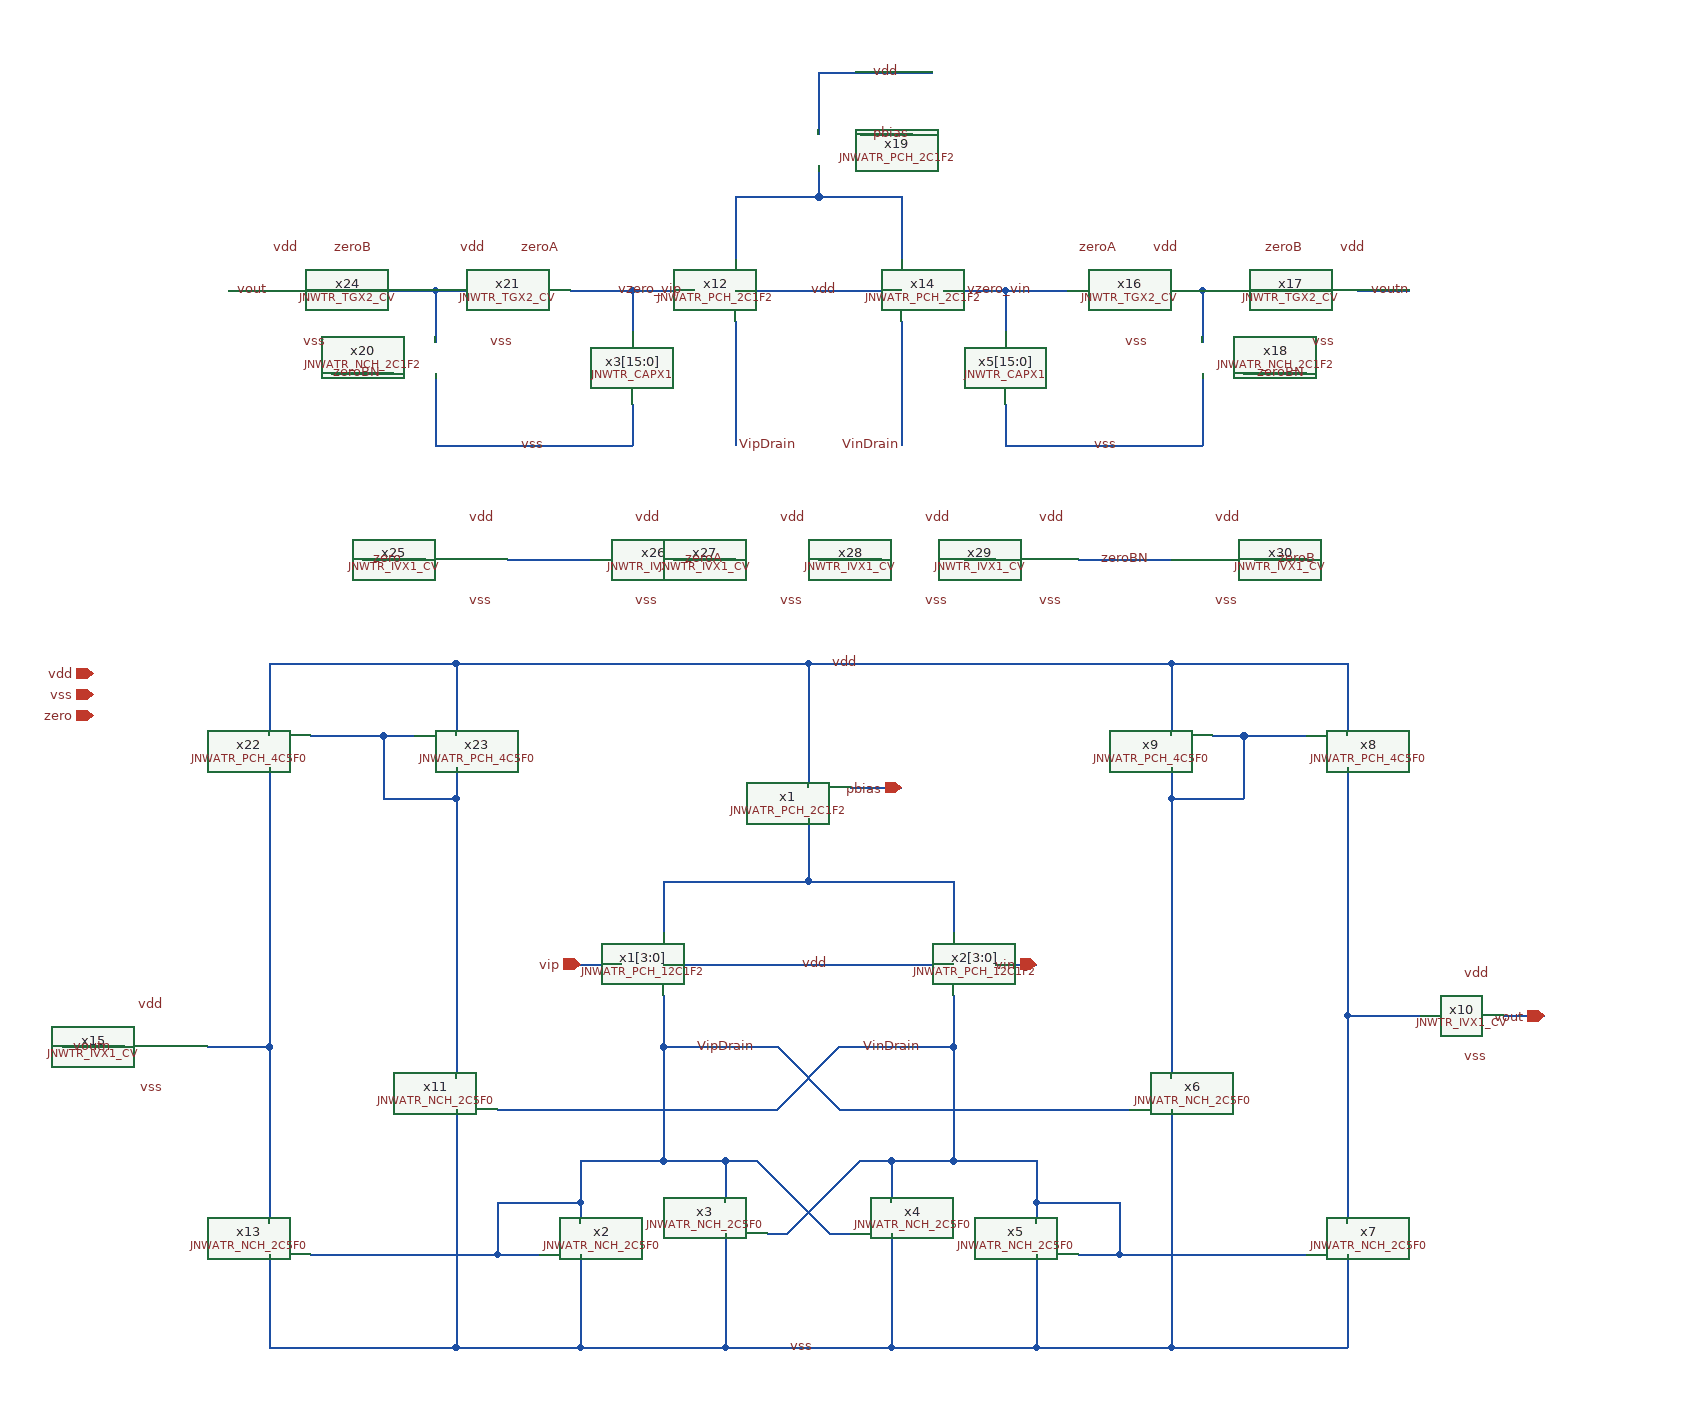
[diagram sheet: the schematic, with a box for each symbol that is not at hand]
v {xschem version=3.4.6RC file_version=1.2
}
G {}
K {}
V {}
S {}
E {}
N 1590 -800 1590 -740 {
lab=#net1}
N 1630 -830 1680 -830 {
lab=pbias}
N 1370 -660 1410 -660 {
lab=vip}
N 1770 -660 1810 -660 {
lab=vin}
N 1450 -580 1450 -470 {
lab=VipDrain}
N 1370 -430 1370 -410 {
lab=VipDrain}
N 1370 -470 1450 -470 {
lab=VipDrain}
N 1450 -470 1510 -470 {
lab=VipDrain}
N 1510 -470 1510 -430 {
lab=VipDrain}
N 1730 -580 1730 -470 {
lab=VinDrain}
N 1670 -470 1670 -430 {
lab=VinDrain}
N 1670 -470 1730 -470 {
lab=VinDrain}
N 1730 -470 1810 -470 {
lab=VinDrain}
N 1810 -430 1810 -410 {
lab=VinDrain}
N 1550 -400 1570 -400 {
lab=VinDrain}
N 1570 -400 1640 -470 {
lab=VinDrain}
N 1610 -400 1630 -400 {
lab=VipDrain}
N 1540 -470 1610 -400 {
lab=VipDrain}
N 1510 -470 1540 -470 {
lab=VipDrain}
N 1640 -470 1670 -470 {
lab=VinDrain}
N 1510 -400 1510 -290 {
lab=vss}
N 1670 -400 1670 -290 {
lab=vss}
N 1370 -290 1510 -290 {
lab=vss}
N 1510 -290 1670 -290 {
lab=vss}
N 1670 -290 1810 -290 {
lab=vss}
N 1810 -380 1810 -290 {
lab=vss}
N 1370 -380 1370 -290 {
lab=vss}
N 1890 -430 1890 -380 {
lab=VinDrain}
N 1810 -430 1890 -430 {
lab=VinDrain}
N 1810 -470 1810 -430 {
lab=VinDrain}
N 1850 -380 1890 -380 {
lab=VinDrain}
N 2110 -380 2110 -290 {
lab=vss}
N 2010 -880 2010 -820 {
lab=#net2}
N 2010 -880 2070 -880 {
lab=#net2}
N 1940 -950 1940 -880 {
lab=vdd}
N 2110 -950 2110 -880 {
lab=vdd}
N 1250 -950 1590 -950 {
lab=vdd}
N 1250 -290 1370 -290 {
lab=vss}
N 1590 -950 1590 -830 {
lab=vdd}
N 1450 -740 1450 -690 {
lab=#net1}
N 1730 -740 1730 -690 {
lab=#net1}
N 1450 -660 1730 -660 {
lab=vdd}
N 1450 -740 1590 -740 {
lab=#net1}
N 1590 -740 1730 -740 {
lab=#net1}
N 1940 -950 2110 -950 {
lab=vdd}
N 1940 -850 1940 -820 {
lab=#net2}
N 1940 -820 2010 -820 {
lab=#net2}
N 1890 -380 2070 -380 {
lab=VinDrain}
N 1590 -950 1940 -950 {
lab=vdd}
N 1940 -290 2110 -290 {
lab=vss}
N 1940 -820 1940 -550 {
lab=#net2}
N 1940 -520 1940 -290 {
lab=vss}
N 1810 -290 1940 -290 {
lab=vss}
N 1620 -520 1900 -520 {
lab=VipDrain}
N 1560 -580 1620 -520 {
lab=VipDrain}
N 1450 -580 1560 -580 {
lab=VipDrain}
N 1450 -630 1450 -580 {
lab=VipDrain}
N 1980 -880 2010 -880 {
lab=#net2}
N 1070 -380 1070 -290 {
lab=vss}
N 1180 -880 1180 -820 {
lab=#net3}
N 1110 -880 1180 -880 {
lab=#net3}
N 1250 -950 1250 -880 {
lab=vdd}
N 1070 -950 1070 -880 {
lab=vdd}
N 1070 -950 1250 -950 {
lab=vdd}
N 1250 -850 1250 -820 {
lab=#net3}
N 1070 -580 1070 -410 {
lab=#net4}
N 1180 -820 1250 -820 {
lab=#net3}
N 1070 -290 1250 -290 {
lab=vss}
N 1250 -820 1250 -550 {
lab=#net3}
N 1250 -520 1250 -290 {
lab=vss}
N 1180 -880 1210 -880 {
lab=#net3}
N 1290 -380 1330 -380 {
lab=VipDrain}
N 1290 -430 1290 -380 {
lab=VipDrain}
N 1110 -380 1290 -380 {
lab=VipDrain}
N 1290 -430 1370 -430 {
lab=VipDrain}
N 1370 -470 1370 -430 {
lab=VipDrain}
N 1290 -520 1560 -520 {
lab=VinDrain}
N 1560 -520 1620 -580 {
lab=VinDrain}
N 1620 -580 1730 -580 {
lab=VinDrain}
N 1730 -630 1730 -580 {
lab=VinDrain}
N 1010 -580 1070 -580 {
lab=#net4}
N 1070 -850 1070 -580 {
lab=#net4}
N 2110 -610 2110 -410 {
lab=#net5}
N 2110 -610 2180 -610 {
lab=#net5}
N 2110 -850 2110 -610 {
lab=#net5}
N 2120 -1310 2170 -1310 {
lab=voutn}
N 1600 -1400 1680 -1400 {
lab=#net6}
N 1600 -1430 1600 -1400 {
lab=#net6}
N 1640 -1460 1690 -1460 {
lab=pbias}
N 1520 -1400 1600 -1400 {
lab=#net6}
N 1600 -1520 1600 -1460 {
lab=vdd}
N 1600 -1520 1710 -1520 {
lab=vdd}
N 1720 -1310 1780 -1310 {
lab=vzero_vin}
N 1780 -1310 1780 -1270 {
lab=vzero_vin}
N 1780 -1310 1840 -1310 {
lab=vzero_vin}
N 1970 -1310 2020 -1310 {
lab=#net7}
N 1970 -1310 1970 -1260 {
lab=#net7}
N 1940 -1310 1970 -1310 {
lab=#net7}
N 1970 -1230 1970 -1160 {
lab=vss}
N 1780 -1160 1970 -1160 {
lab=vss}
N 1780 -1200 1780 -1160 {
lab=vss}
N 1030 -1310 1080 -1310 {
lab=vout}
N 1420 -1310 1480 -1310 {
lab=vzero_vip}
N 1420 -1310 1420 -1270 {
lab=vzero_vip}
N 1360 -1310 1420 -1310 {
lab=vzero_vip}
N 1180 -1310 1230 -1310 {
lab=#net8}
N 1230 -1310 1230 -1260 {
lab=#net8}
N 1230 -1310 1260 -1310 {
lab=#net8}
N 1230 -1230 1230 -1160 {
lab=vss}
N 1230 -1160 1420 -1160 {
lab=vss}
N 1420 -1200 1420 -1160 {
lab=vss}
N 1520 -1310 1680 -1310 {
lab=vdd}
N 1520 -1400 1520 -1340 {
lab=#net6}
N 1680 -1400 1680 -1340 {
lab=#net6}
N 1520 -1280 1520 -1160 {
lab=VipDrain}
N 1680 -1280 1680 -1160 {
lab=VinDrain}
N 1300 -1050 1380 -1050 {
lab=#net9}
N 1460 -1050 1520 -1050 {
lab=zeroA}
N 1600 -1050 1660 -1050 {
lab=#net10}
N 1740 -1050 1770 -1050 {
lab=#net11}
N 1850 -1050 1940 -1050 {
lab=zeroBN}
N 2020 -1050 2070 -1050 {
lab=zeroB}
N 1160 -1050 1220 -1050 {
lab=zero}
N 2010 -1230 2070 -1230 {
lab=zeroBN}
N 1130 -1230 1190 -1230 {
lab=zeroBN}
N 2260 -610 2300 -610 {
lab=vout}
N 870 -580 930 -580 {
lab=voutn}
C {devices/ipin.sym} 900 -920 0 0 {name=p2 lab=vss
}
C {devices/ipin.sym} 900 -940 0 0 {name=p3 lab=vdd
}
C {JNW_ATR_SKY130A/JNWATR_PCH_12C1F2.sym} 1410 -660 0 0 {name=x1[3:0]}
C {JNW_ATR_SKY130A/JNWATR_PCH_12C1F2.sym} 1770 -660 0 1 {name=x2[3:0]}
C {devices/ipin.sym} 1680 -830 2 0 {name=p1 lab=pbias
}
C {JNW_ATR_SKY130A/JNWATR_PCH_2C1F2.sym} 1630 -830 0 1 {name=x1}
C {devices/ipin.sym} 1810 -660 2 0 {name=p5 lab=vin
}
C {devices/ipin.sym} 1370 -660 0 0 {name=p6 lab=vip
}
C {JNW_ATR_SKY130A/JNWATR_NCH_2C5F0.sym} 1330 -380 0 0 {name=x2 }
C {JNW_ATR_SKY130A/JNWATR_NCH_2C5F0.sym} 1550 -400 0 1 {name=x3 }
C {JNW_ATR_SKY130A/JNWATR_NCH_2C5F0.sym} 1630 -400 0 0 {name=x4 }
C {JNW_ATR_SKY130A/JNWATR_NCH_2C5F0.sym} 1850 -380 0 1 {name=x5 }
C {JNW_ATR_SKY130A/JNWATR_NCH_2C5F0.sym} 1900 -520 0 0 {name=x6 }
C {JNW_ATR_SKY130A/JNWATR_NCH_2C5F0.sym} 2070 -380 0 0 {name=x7 }
C {JNW_ATR_SKY130A/JNWATR_PCH_4C5F0.sym} 2070 -880 0 0 {name=x8 }
C {JNW_ATR_SKY130A/JNWATR_PCH_4C5F0.sym} 1980 -880 0 1 {name=x9 }
C {devices/opin.sym} 2300 -610 2 1 {name=p7 lab=vout}
C {devices/lab_wire.sym} 1610 -660 0 0 {name=p4 sig_type=std_logic lab=vdd}
C {JNW_TR_SKY130A/JNWTR_IVX1_CV.sym} 2180 -610 0 0 {name=x10 }
C {devices/lab_wire.sym} 2220 -650 0 1 {name=p18 sig_type=std_logic lab=vdd}
C {devices/lab_wire.sym} 2220 -570 0 1 {name=p19 sig_type=std_logic lab=vss}
C {JNW_TR_SKY130A/JNWTR_IVX1_CV.sym} 1010 -580 0 1 {name=x15 }
C {devices/lab_wire.sym} 970 -620 0 0 {name=p23 sig_type=std_logic lab=vdd}
C {devices/lab_wire.sym} 970 -540 0 0 {name=p24 sig_type=std_logic lab=vss}
C {devices/lab_wire.sym} 920 -580 0 0 {name=p28 sig_type=std_logic lab=voutn}
C {devices/ipin.sym} 900 -900 0 0 {name=p11 lab=zero
}
C {devices/lab_wire.sym} 1610 -950 0 1 {name=p8 sig_type=std_logic lab=vdd}
C {devices/lab_wire.sym} 1570 -290 0 1 {name=p9 sig_type=std_logic lab=vss}
C {JNW_ATR_SKY130A/JNWATR_NCH_2C5F0.sym} 1290 -520 0 1 {name=x11 }
C {JNW_ATR_SKY130A/JNWATR_NCH_2C5F0.sym} 1110 -380 0 1 {name=x13 }
C {JNW_ATR_SKY130A/JNWATR_PCH_4C5F0.sym} 1110 -880 0 1 {name=x22 }
C {JNW_ATR_SKY130A/JNWATR_PCH_4C5F0.sym} 1210 -880 0 0 {name=x23 }
C {devices/lab_wire.sym} 1700 -580 0 0 {name=p12 sig_type=std_logic lab=VinDrain}
C {devices/lab_wire.sym} 1480 -580 0 1 {name=p13 sig_type=std_logic lab=VipDrain}
C {JNW_ATR_SKY130A/JNWATR_PCH_2C1F2.sym} 1480 -1310 0 0 {name=x12 }
C {JNW_ATR_SKY130A/JNWATR_PCH_2C1F2.sym} 1720 -1310 0 1 {name=x14 }
C {JNW_ATR_SKY130A/JNWATR_NCH_2C1F2.sym} 2010 -1230 0 1 {name=x18 }
C {JNW_TR_SKY130A/JNWTR_CAPX1.sym} 1780 -1210 0 0 {name=x5[15:0]}
C {JNW_TR_SKY130A/JNWTR_TGX2_CV.sym} 1830 -1310 0 0 {name=x16 }
C {JNW_TR_SKY130A/JNWTR_TGX2_CV.sym} 2010 -1310 0 0 {name=x17 }
C {devices/lab_wire.sym} 2130 -1310 0 1 {name=p14 sig_type=std_logic lab=voutn}
C {JNW_ATR_SKY130A/JNWATR_PCH_2C1F2.sym} 1640 -1460 0 1 {name=x19}
C {devices/lab_wire.sym} 1650 -1460 0 1 {name=p16 sig_type=std_logic lab=pbias}
C {devices/lab_wire.sym} 1650 -1520 0 1 {name=p15 sig_type=std_logic lab=vdd}
C {devices/lab_wire.sym} 1920 -1350 0 1 {name=p17 sig_type=std_logic lab=vdd}
C {devices/lab_wire.sym} 2100 -1350 0 1 {name=p20 sig_type=std_logic lab=vdd}
C {devices/lab_wire.sym} 1920 -1260 0 0 {name=p21 sig_type=std_logic lab=vss}
C {devices/lab_wire.sym} 2100 -1260 0 0 {name=p22 sig_type=std_logic lab=vss}
C {devices/lab_wire.sym} 1890 -1160 0 0 {name=p25 sig_type=std_logic lab=vss}
C {JNW_ATR_SKY130A/JNWATR_NCH_2C1F2.sym} 1190 -1230 0 0 {name=x20 }
C {JNW_TR_SKY130A/JNWTR_CAPX1.sym} 1420 -1210 0 1 {name=x3[15:0]}
C {JNW_TR_SKY130A/JNWTR_TGX2_CV.sym} 1370 -1310 0 1 {name=x21 }
C {JNW_TR_SKY130A/JNWTR_TGX2_CV.sym} 1190 -1310 0 1 {name=x24 }
C {devices/lab_wire.sym} 1070 -1310 0 0 {name=p26 sig_type=std_logic lab=vout}
C {devices/lab_wire.sym} 1280 -1350 0 0 {name=p27 sig_type=std_logic lab=vdd}
C {devices/lab_wire.sym} 1100 -1350 0 0 {name=p29 sig_type=std_logic lab=vdd}
C {devices/lab_wire.sym} 1280 -1260 0 1 {name=p30 sig_type=std_logic lab=vss}
C {devices/lab_wire.sym} 1100 -1260 0 1 {name=p31 sig_type=std_logic lab=vss}
C {devices/lab_wire.sym} 1310 -1160 0 1 {name=p32 sig_type=std_logic lab=vss}
C {devices/lab_wire.sym} 1590 -1310 0 1 {name=p33 sig_type=std_logic lab=vdd}
C {devices/lab_wire.sym} 1520 -1160 0 1 {name=p34 sig_type=std_logic lab=VipDrain}
C {devices/lab_wire.sym} 1680 -1160 0 0 {name=p35 sig_type=std_logic lab=VinDrain}
C {JNW_TR_SKY130A/JNWTR_IVX1_CV.sym} 1220 -1050 0 0 {name=x25 }
C {devices/lab_wire.sym} 1260 -1090 0 1 {name=p36 sig_type=std_logic lab=vdd}
C {devices/lab_wire.sym} 1260 -1010 0 1 {name=p37 sig_type=std_logic lab=vss}
C {JNW_TR_SKY130A/JNWTR_IVX1_CV.sym} 1380 -1050 0 0 {name=x26 }
C {devices/lab_wire.sym} 1420 -1090 0 1 {name=p38 sig_type=std_logic lab=vdd}
C {devices/lab_wire.sym} 1420 -1010 0 1 {name=p39 sig_type=std_logic lab=vss}
C {JNW_TR_SKY130A/JNWTR_IVX1_CV.sym} 1520 -1050 0 0 {name=x27 }
C {devices/lab_wire.sym} 1560 -1090 0 1 {name=p40 sig_type=std_logic lab=vdd}
C {devices/lab_wire.sym} 1560 -1010 0 1 {name=p41 sig_type=std_logic lab=vss}
C {JNW_TR_SKY130A/JNWTR_IVX1_CV.sym} 1660 -1050 0 0 {name=x28 }
C {devices/lab_wire.sym} 1700 -1090 0 1 {name=p42 sig_type=std_logic lab=vdd}
C {devices/lab_wire.sym} 1700 -1010 0 1 {name=p43 sig_type=std_logic lab=vss}
C {JNW_TR_SKY130A/JNWTR_IVX1_CV.sym} 1770 -1050 0 0 {name=x29 }
C {devices/lab_wire.sym} 1810 -1090 0 1 {name=p44 sig_type=std_logic lab=vdd}
C {devices/lab_wire.sym} 1810 -1010 0 1 {name=p45 sig_type=std_logic lab=vss}
C {JNW_TR_SKY130A/JNWTR_IVX1_CV.sym} 1940 -1050 0 0 {name=x30 }
C {devices/lab_wire.sym} 1980 -1090 0 1 {name=p46 sig_type=std_logic lab=vdd}
C {devices/lab_wire.sym} 1980 -1010 0 1 {name=p47 sig_type=std_logic lab=vss}
C {devices/lab_wire.sym} 1200 -1050 0 0 {name=p48 sig_type=std_logic lab=zero}
C {devices/lab_wire.sym} 1510 -1050 0 0 {name=p49 sig_type=std_logic lab=zeroA}
C {devices/lab_wire.sym} 2040 -1050 0 1 {name=p50 sig_type=std_logic lab=zeroB}
C {devices/lab_wire.sym} 1870 -1050 0 1 {name=p51 sig_type=std_logic lab=zeroBN}
C {devices/lab_wire.sym} 2020 -1230 0 1 {name=p52 sig_type=std_logic lab=zeroBN}
C {devices/lab_wire.sym} 1180 -1230 0 0 {name=p53 sig_type=std_logic lab=zeroBN}
C {devices/lab_wire.sym} 1890 -1350 0 0 {name=p54 sig_type=std_logic lab=zeroA}
C {devices/lab_wire.sym} 1310 -1350 0 1 {name=p55 sig_type=std_logic lab=zeroA}
C {devices/lab_wire.sym} 2070 -1350 0 0 {name=p56 sig_type=std_logic lab=zeroB}
C {devices/lab_wire.sym} 1130 -1350 0 1 {name=p57 sig_type=std_logic lab=zeroB}
C {devices/lab_wire.sym} 1740 -1310 0 1 {name=p10 sig_type=std_logic lab=vzero_vin}
C {devices/lab_wire.sym} 1470 -1310 0 0 {name=p58 sig_type=std_logic lab=vzero_vip}
